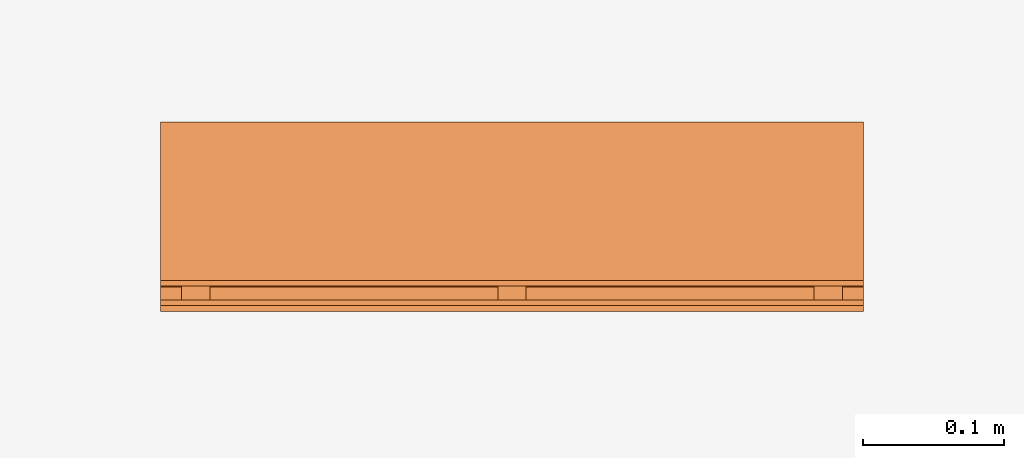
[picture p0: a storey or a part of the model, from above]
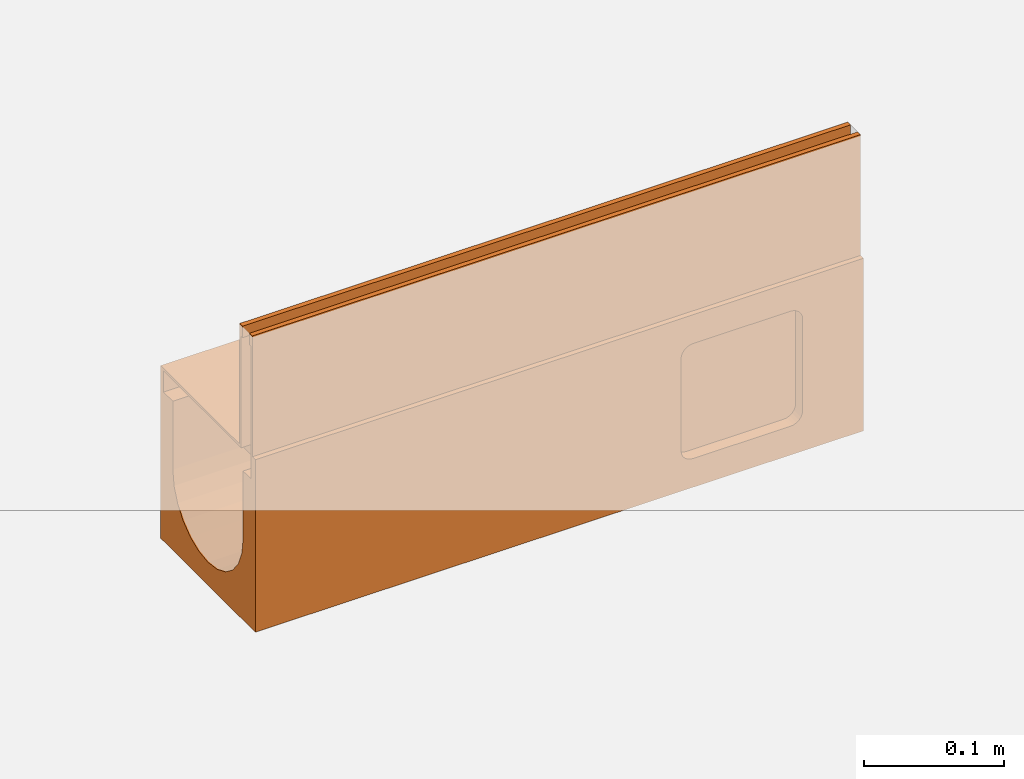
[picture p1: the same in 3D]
Properties of the parts of a building model (IFC2X3)

# File
Description: ViewDefinition [CoordinationView]
File name: 23050 - No 0.1J Constant Depth Channel - 500mm LG - Invert Depth 130mm.ifc
Time: 2013-10-31T17:30:40
Written by: Autodesk Revit 2013
Made in: 20120221_2030(x64)

# IfcProject, Project Number
LongName: Project Name; Phase: Project Status

# IfcSite, Default
RefLatitude: 42, 21, 30, 344238; RefLongitude: -71, -3, -35, -194702; RefElevation: 0 mm

# IfcBuilding
Pset_BuildingCommon - NumberOfStoreys: 1
Other - Project Issue Date: Issue Date; Project Status: Project Status; Project Name: Project Name; Project Number: Project Number; Project Address: ## Street City, State Zip; Client Name: Owner

# IfcBuildingStorey, Level 1
LongName: Level 1; Elevation: 0 mm
Constraints - Elevation Base: 0; Elevation: 0 mm
Graphics - Line Weight: 1; Symbol at End 1 Default: no; Symbol at End 2 Default: yes; Color: 0; Line Pattern: Center; Symbol: M_Level Head - Circle: M_Level Head - Circle
Identity Data - Building Story: yes; Structural: no; Name: Level 1
Dimensions - Computation Height: 0 mm

# IfcBuildingElementProxy: 23050 - No 0.1J Constant Depth Channel - 500mm LG - Invert Depth 130mm, Civil-Drainage-Channel-ACO-MultiDrain-M100D-Brickslot-Channel-System:23050 - No 0.1J Constant Depth Channel - 500mm LG - Invert Depth 130mm:23050 - No 0.1J Constant Depth Channel - 500mm LG - Invert Depth 130mm:196059
In: Level 1
Material: Steel, Galvanized, Vienite® Synthetic Resin Concrete
Construction - 23461_Load Class C250_Brickslot Grating_Galvanized Steel_500mm Long: no; 23460_Load Class C250_Brickslot Grating_Galvanized Steel_1000mm Long: no; 23465_Load Class D400_Brickslot Grating_Galvanized Steel_1000mm Long: yes; 23467_Load Class D400_Brickslot Access Unit_Galvanised Steel_500mm Long: no; 23466_Load Class D400_Brickslot Grating_Galvanized Steel_500mm Long: no; 23404_Universal Endcap (Female End): no; 23404_Universal Endcap (Male End): no; 23462_Load Class C250_Brickslot Access Unit_Galvanised Steel_500mm Long: no; Sloping Channel: no; Constant Depth Channel: no; Shallow Depth Channel: no; 23410_Sump Unit: no; Constant Depth Junction Channel: yes; Shallow Depth Channel with seal: no
Dimensions - Length: 1000 mm; Volume: 4009204 mm3; FloorCut_Length: -500 mm; EndCap Position: 500 mm; Brickslot Void Depth: 0 mm; Custom_Void_length: 500 mm; Brickslot Access Unit Void Bottom Depth: -6605 mm; Brickslot Void Length: 500 mm; Brickslot Access Unit Void Depth: -6500 mm; SlopingEndOverallDepth: 250 mm; Brickslot Access Unit Floor Cut Length: 500 mm; SlopingOverallDepth: 245 mm; Floor Cut Gap: 105 mm; SlopingInvertDepth: 175 mm; EndCap_Height: 150 mm; SlopingEndInvertDepth: 180 mm; ShallowInvDepth: 55 mm; Depth: 150 mm; FloorCut_Depth: 150 mm; Length Drain: -500 mm; InvDepth: 80 mm; ShallowOverallDepth: 75 mm; Access_Custom_Void_Length: 0 mm; FloorCut_Width: 135 mm; GratingLength: -1000 mm
Phasing - Phase Created: New Construction
Constraints - Moves With Nearby Elements: no; Level: Level: Level 1
Pset_BuildingElementProxyCommon - Reference: 23050 - No 0.1J Constant Depth Channel - 500mm LG - Invert Depth 130mm
Data - Concrete Surround Volume - Load Class A 15 - Concrete Pavement: 0.07m³/m; Channel C.S.A: 0.009m²; Product Weight: 7.6Kg; Load Class: A 15 - D 400; Invert Depth: 130mm; Concrete Surround Volume - Load Class D 400 - Concrete Pavement: 0.17m³/m; Pre-formed Outlet Ø: N/A; Hydraulic Performance: http://www.aco.co.uk/download.php?id=173; Concrete Surround Volume - Load Class B 125 - C 250 - Concrete Pavement: 0.11m³/m; Product Dimensions: 500mm x 135mm x 150mm (LxWxH); ACO Hydraulic Design Software: http://www.acodesign.co.uk; Product Standard: BS EN 1433:2002, CE marked; Installation - Concrete Grade: Refer to brochure
Materials and Finishes - Channel Material: Vienite® Synthetic Resin Concrete; Edge Rail Colour: Silver; Edge Rail Finish: Pre-galvanised; Edge Rail Material: Steel; Channel Colour: Brown
General - SerialNumber: 0; TagNumber: 0
Identity Data - e-mail Sales: customersupport@aco.co.uk; e-mail Technical: technical@aco.co.uk; Cost: 0; Price: POA - contact ACO; OmniClass Title: Rainwater Removal; Model Description: Channel drainage system; Watermarked With: BIM Manager Premium Suite; Maintenance guidelines: http://www.aco.co.uk/download.php?id=173; Product Code: 23050; URL: www.aco.co.uk; Watermark 2: This file is water marked and users are prohibited to reproduce, adapt, distribute this information; Product Page URL: http://www.aco.co.uk/product_detail.php?id=58; Type Comments: ACO MultiDrain M100D 0.1J Constant Depth Junction Channel 500mm Long; Watermark 1: This file is the property of ACO Technologies PLC; Address: ACO Business Park, Hitchin Road, Shefford, Bedfordshire, United Kingdom SG17 5TE; Installation guidelines: http://www.aco.co.uk/download.php?id=173; Product brochure: http://www.aco.co.uk/download.php?id=173; OmniClass Number: 23.70.50.24; Model: ACO MultiDrain MD Brickslot- M100D; Assembly Code: D2040; Manufacturer: ACO Technologies plc - ACO Water Management Division; Fax: +44 (0)1462 815895; Telephone: +44 (0)1462 816666; Assembly Description: Rain Water Drainage
Model Properties - Brickslot Grating Product code 23466: Load Class D400 - Brickslot Galvanised Steel - 500mm long x 105mm high - 10mm Slot - Intake area - 10000mm²/m - 3.3 Kg; Brickslot Grating Product code 23465: N/A; Brickslot Access Unit Product code 23467: Load Class D400 - Brickslot Access Unit Galvanised Steel - 500mm long x 105mm high - 10mm Slot - Intake area - 10000mm²/m - 6.4 Kg; End Cap Product code 23404: No 306 Universal End Cap - 135mm wide x 300mm long - Spigot Ø110mm x 50mm long - Silver - Polypropylene - 0.16kg; Brickslot Grating Product code 23461: Load Class C250 - Brickslot Galvanised Steel - 500mm long x 105mm high - 10mm Slot - Intake area - 10000mm²/m -3.3 Kg; Brickslot Grating Product code 23460: N/A; Brickslot Access Unit Product code 23462: Load Class C250 - Brickslot Access Unit Galvanised Steel - 500mm long x 105mm high - 10mm Slot - Intake area - 10000mm²/m - 6.4 Kg
Green Building Properties - Edge Rail Recycled Material Content: Between 40% - 90%; Channel Recyclable: Fully recyclable; Channel Recycled Material Content: 20% minimum; Edge Rail Recyclable: Fully recyclable
Other - Created By: www.aco.co.uk; Revision: 1; Watermarked By: www.aco.co.uk

# IfcOpeningElement: Recess (2)
In: Level 1
Dimensions - Area: 25000000 mm2; Thickness: 1000 mm; Volume: 24988930000 mm3; Perimeter: 20000 mm
Constraints - Level: Level: Level 1; Related to Mass: no; Height Offset From Level: 0 mm; Room Bounding: yes
Phasing - Phase Created: New Construction
Structural - Enable Analytical Model: no; Structural: no
Analytical Properties - Thermal mass: 1359800; Absorptance: 0.1; Heat Transfer Coefficient (U): 0.837; Roughness: 1; Thermal Resistance (R): 1.19474
Construction - Function: 0; Default Thickness: 1000 mm
Materials and Finishes - Structural Material: Earth
Graphics - Coarse Scale Fill Color: 0

# IfcSlab: Floor:Generic Floor - 1000mm, Floor:Generic Floor - 1000mm:193825
In: Level 1
PredefinedType: FLOOR; Material: Earth 1000 mm
Dimensions - Area: 25000000 mm2; Thickness: 1000 mm; Volume: 24988930000 mm3; Perimeter: 20000 mm
Constraints - Level: Level: Level 1; Related to Mass: no; Height Offset From Level: 0 mm; Room Bounding: yes
Phasing - Phase Created: New Construction
Structural - Enable Analytical Model: no; Structural: no
Pset_SlabCommon - Reference: Generic Floor - 1000mm; IsExternal: no; LoadBearing: yes
Analytical Properties - Thermal mass: 1359800; Absorptance: 0.1; Heat Transfer Coefficient (U): 0.837; Roughness: 1; Thermal Resistance (R): 1.19474
Construction - Function: 0; Default Thickness: 1000 mm
Materials and Finishes - Structural Material: Earth
Graphics - Coarse Scale Fill Color: 0
